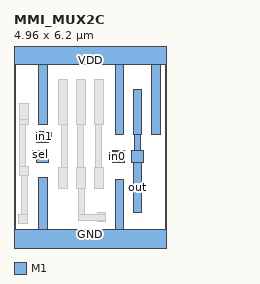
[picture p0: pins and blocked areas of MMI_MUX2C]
MACRO MMI_MUX2C
	CLASS CORE ;
	FOREIGN MMI_MUX2C 0 0 ;
	SIZE 4.96 BY 6.2 ;
	SYMMETRY X Y ;
	SITE CORE1 ;
	PIN out
		DIRECTION output ;
		USE SIGNAL ;
		PORT
			LAYER M1 ;
			RECT 3.895 3.495 4.175 4.965 ;
			LAYER M1 ;
			RECT 3.93 2.98 4.125 3.495 ;
			LAYER M1 ;
			RECT 3.84 2.6 4.22 2.98 ;
			LAYER M1 ;
			RECT 3.895 0.975 4.175 2.6 ;
		END
		AntennaDiffArea 1.2859 ;
	END out
	PIN sel
		DIRECTION input ;
		USE SIGNAL ;
		PORT
			LAYER M1 ;
			RECT 0.595 2.98 0.875 2.99 ;
			LAYER M1 ;
			RECT 0.595 2.71 1.12 2.98 ;
			LAYER M1 ;
			RECT 0.745 2.6 1.12 2.71 ;
		END
		AntennaGateArea 0.51975 ;
	END sel
	PIN in1
		DIRECTION input ;
		USE SIGNAL ;
		PORT
			LAYER M1 ;
			RECT 0.745 3.57 1.125 3.615 ;
			LAYER M1 ;
			RECT 0.745 3.29 1.225 3.57 ;
			LAYER M1 ;
			RECT 0.745 3.24 1.125 3.29 ;
		END
		AntennaGateArea 0.34575 ;
	END in1
	PIN GND
		DIRECTION inout ;
		USE GROUND ;
		PORT
			LAYER M1 ;
			RECT 0.81 0.42 1.095 2.09 ;
			LAYER M1 ;
			RECT 3.305 0.42 3.585 2.035 ;
			LAYER M1 ;
			RECT 0 -0.42 4.96 0.42 ;
		END
	END GND
	PIN VDD
		DIRECTION inout ;
		USE POWER ;
		PORT
			LAYER M1 ;
			RECT 0 5.78 4.96 6.62 ;
			LAYER M1 ;
			RECT 0.815 3.835 1.095 5.78 ;
			LAYER M1 ;
			RECT 3.305 3.495 3.585 5.78 ;
			LAYER M1 ;
			RECT 4.485 3.495 4.765 5.78 ;
		END
	END VDD
	PIN in0
		DIRECTION input ;
		USE SIGNAL ;
		PORT
			LAYER M1 ;
			RECT 3.22 2.94 3.6 2.985 ;
			LAYER M1 ;
			RECT 3.13 2.66 3.6 2.94 ;
			LAYER M1 ;
			RECT 3.22 2.6 3.6 2.66 ;
		END
		AntennaGateArea 0.3465 ;
	END in0
	OBS
		LAYER M1 ;
		RECT 0.18 4.01 0.46 4.535 ;
		LAYER M1 ;
		RECT 0.175 3.835 0.46 4.01 ;
		LAYER M1 ;
		RECT 1.455 3.835 1.735 5.305 ;
		LAYER M1 ;
		RECT 2.045 3.835 2.325 5.305 ;
		LAYER M1 ;
		RECT 2.635 3.835 2.915 5.305 ;
		LAYER M1 ;
		RECT 0.175 2.47 0.37 3.835 ;
		LAYER M1 ;
		RECT 0.175 2.185 0.46 2.47 ;
		LAYER M1 ;
		RECT 1.54 2.445 1.73 3.835 ;
		LAYER M1 ;
		RECT 2.085 2.445 2.275 3.835 ;
		LAYER M1 ;
		RECT 2.675 2.445 2.865 3.835 ;
		LAYER M1 ;
		RECT 0.18 2.155 0.46 2.185 ;
		LAYER M1 ;
		RECT 0.23 0.9 0.425 2.155 ;
		LAYER M1 ;
		RECT 0.155 0.62 0.435 0.9 ;
		LAYER M1 ;
		RECT 1.455 1.745 1.735 2.445 ;
		LAYER M1 ;
		RECT 2.045 1.745 2.325 2.445 ;
		LAYER M1 ;
		RECT 2.635 1.745 2.915 2.445 ;
		LAYER M1 ;
		RECT 2.1 0.895 2.29 1.745 ;
		LAYER M1 ;
		RECT 2.72 0.895 3 0.95 ;
		LAYER M1 ;
		RECT 2.1 0.705 3 0.895 ;
		LAYER M1 ;
		RECT 2.72 0.67 3 0.705 ;
	END
END MMI_MUX2C
